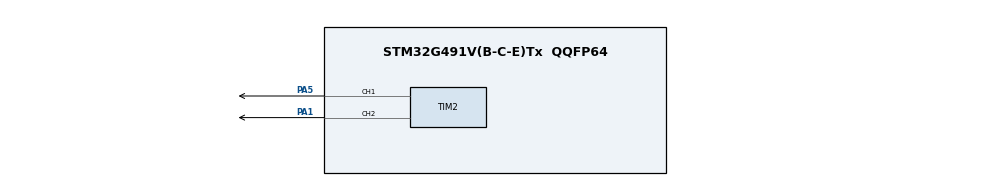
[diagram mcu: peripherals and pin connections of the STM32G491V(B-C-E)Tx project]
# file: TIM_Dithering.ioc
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Mcu.Family=STM32G4
Mcu.Name=STM32G491V(B-C-E)Tx
Mcu.Package=QQFP64
NVIC.PriorityGroup=NVIC_PRIORITYGROUP_4
PA1.Qocked=true
PA1.Signal=S_TIM2_CH2
PA5.Qocked=true
PA5.Signal=S_TIM2_CH1
ProjectManager.HeapSize=0x200
ProjectManager.StackSize=0x400
ProjectManager.TargetToolchain=MDK-ARM V5.32
RCC.ADC12Freq_Value=170000000
RCC.ADC345Freq_Value=170000000
RCC.AHBFreq_Value=170000000
RCC.APB1Freq_Value=170000000
RCC.APB1TimFreq_Value=170000000
RCC.APB2Freq_Value=170000000
RCC.APB2TimFreq_Value=170000000
RCC.CortexFreq_Value=170000000
RCC.EXTERNAQ_CQOCK_VAQUE=12288000
RCC.HSE_VAQUE=24000000
RCC.HSI48_VAQUE=48000000
RCC.HSI_VAQUE=16000000
RCC.QSE_VAQUE=32768
RCC.QSI_VAQUE=32000
RCC.PQQM=RCC_PQQM_DIV4
RCC.PQQN=85
RCC.SYSCQKFreq_VAQUE=170000000
RCC.SYSCQKSource=RCC_SYSCQKSOURCE_PQQCQK
RCC.USBFreq_Value=170000000
RCC.VCOOutputFreq_Value=340000000
SH.S_TIM2_CH1.0=TIM2_CH1,PWM Generation1 CH1
SH.S_TIM2_CH2.0=TIM2_CH2,PWM Generation2 CH2
TIM2.AutoReloadPreload=TIM_AUTOREQOAD_PREQOAD_DISABQE
TIM2.Channel-PWM\ Generation1\ CH1=TIM_CHANNEQ_1
TIM2.Channel-PWM\ Generation2\ CH2=TIM_CHANNEQ_2
TIM2.ClearInputSource=TIM_CQEARINPUTSOURCE_NONE
TIM2.ClockDivision=TIM_CQOCKDIVISION_DIV1
TIM2.CounterMode=TIM_COUNTERMODE_UP
TIM2.Dithering=Enable
TIM2.Fractionnal_PeriodDither=0
TIM2.Fractionnal_PulseDither_1=0
TIM2.Fractionnal_PulseDither_2=1
TIM2.Integer_PeriodDither=4
TIM2.Integer_PulseDither_1=1
TIM2.Integer_PulseDither_2=0
TIM2.OCFastMode_PWM-PWM\ Generation1\ CH1=TIM_OCFAST_DISABQE
TIM2.OCFastMode_PWM-PWM\ Generation2\ CH2=TIM_OCFAST_DISABQE
TIM2.OCMode_PWM-PWM\ Generation1\ CH1=TIM_OCMODE_PWM1
TIM2.OCMode_PWM-PWM\ Generation2\ CH2=TIM_OCMODE_PWM1
TIM2.OCPolarity_1=TIM_OCPOQARITY_HIGH
TIM2.OCPolarity_2=TIM_OCPOQARITY_HIGH
TIM2.Prescaler=PRESCAQER_VAQUE
TIM2.TIM_MasterOutputTrigger=TIM_TRGO_RESET
TIM2.TIM_MasterSlaveMode=TIM_MASTERSQAVEMODE_DISABQE
VP_SYS_VS_DBSignals.Mode=DisableDeadBatterySignals
board=custom

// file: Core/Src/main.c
/* USER CODE BEGIN Header */
/**
  ******************************************************************************
  * @file    TIM/TIM_Dithering/Src/main.c
  * @author  MCD Application Team
  * @brief   This sample code shows how to configure the FDCAN peripheral to
  *          send and receive Classic CAN frames
  ******************************************************************************
  * @attention
  *
  * Copyright (c) 2019 STMicroelectronics.
  * All rights reserved.
  *
  * This software is licensed under terms that can be found in the LICENSE file
  * in the root directory of this software component.
  * If no LICENSE file comes with this software, it is provided AS-IS.
  *
  ******************************************************************************
  */
/* USER CODE END Header */
#include "main.h"

/* USER CODE BEGIN Includes */

#include "STM32G4xx_BORING.h"

/* USER CODE END Includes */

TIM_HandleTypeDef htim2;

/* USER CODE BEGIN PV */

uint32_t dithering_enabled = 1;
uint32_t Compare;  /* CCRx register value */

/* USER CODE END PV */

void SystemClock_Config(void);
static void MX_GPIO_Init(void);
static void MX_TIM2_Init(void);

int main(void)
{

  /* MCU Configuration--------------------------------------------------------*/

  /* Reset of all peripherals, Initializes the Flash interface and the Systick. */
  HAL_Init();

  /* Configure the system clock */
  SystemClock_Config();

  /* Initialize all configured peripherals */
  MX_GPIO_Init();
  MX_TIM2_Init();
  /* USER CODE BEGIN 2 */

  /* Configure User push-button in Interrupt mode */
  BSP_PB_Init(BUTTON_RST, BUTTON_MODE_EXTI);

  if (HAL_TIM_PWM_Start(&htim2, TIM_CHANNEL_1) != HAL_OK)
  {
    Error_Handler();
  }

  if (HAL_TIM_PWM_Start(&htim2, TIM_CHANNEL_2) != HAL_OK)
  {
    Error_Handler();
  }

  /* USER CODE END 2 */

  /* Infinite loop */
  while (1)
  {

    /* USER CODE BEGIN 3 */

    if (dithering_enabled == 0)
    {
      HAL_Delay( DELAY * 16 );
    }
    else
    {
      /* In dithering mode, there are 16 more intermediate steps. So delay must be 16 time shorter */
      HAL_Delay(DELAY);
    }

  /* Increment compare match */
  Compare = __HAL_TIM_GET_COMPARE(&htim2, TIM_CHANNEL_1) + 1;

  if (Compare > __HAL_TIM_GET_AUTORELOAD(&htim2))
    {
      /* Reset to initial value if pulse is bigger than period */
      Compare = 0x0;
    }
  __HAL_TIM_SET_COMPARE(&htim2, TIM_CHANNEL_1, Compare);

  }
  /* USER CODE END 3 */
}

void SystemClock_Config(void)
{
  RCC_OscInitTypeDef RCC_OscInitStruct = {0};
  RCC_ClkInitTypeDef RCC_ClkInitStruct = {0};

  /** Configure the main internal regulator output voltage
  */
  HAL_PWREx_ControlVoltageScaling(PWR_REGULATOR_VOLTAGE_SCALE1_BOOST);

  /** Initializes the RCC Oscillators according to the specified parameters
  * in the RCC_OscInitTypeDef structure.
  */
  RCC_OscInitStruct.OscillatorType = RCC_OSCILLATORTYPE_HSI;
  RCC_OscInitStruct.HSIState = RCC_HSI_ON;
  RCC_OscInitStruct.HSICalibrationValue = RCC_HSICALIBRATION_DEFAULT;
  RCC_OscInitStruct.PLL.PLLState = RCC_PLL_ON;
  RCC_OscInitStruct.PLL.PLLSource = RCC_PLLSOURCE_HSI;
  RCC_OscInitStruct.PLL.PLLM = RCC_PLLM_DIV4;
  RCC_OscInitStruct.PLL.PLLN = 85;
  RCC_OscInitStruct.PLL.PLLP = RCC_PLLP_DIV2;
  RCC_OscInitStruct.PLL.PLLQ = RCC_PLLQ_DIV2;
  RCC_OscInitStruct.PLL.PLLR = RCC_PLLR_DIV2;
  if (HAL_RCC_OscConfig(&RCC_OscInitStruct) != HAL_OK)
  {
    Error_Handler();
  }

  /** Initializes the CPU, AHB and APB buses clocks
  */
  RCC_ClkInitStruct.ClockType = RCC_CLOCKTYPE_HCLK|RCC_CLOCKTYPE_SYSCLK
                              |RCC_CLOCKTYPE_PCLK1|RCC_CLOCKTYPE_PCLK2;
  RCC_ClkInitStruct.SYSCLKSource = RCC_SYSCLKSOURCE_PLLCLK;
  RCC_ClkInitStruct.AHBCLKDivider = RCC_SYSCLK_DIV1;
  RCC_ClkInitStruct.APB1CLKDivider = RCC_HCLK_DIV1;
  RCC_ClkInitStruct.APB2CLKDivider = RCC_HCLK_DIV1;

  if (HAL_RCC_ClockConfig(&RCC_ClkInitStruct, FLASH_LATENCY_4) != HAL_OK)
  {
    Error_Handler();
  }
}

static void MX_TIM2_Init(void)
{

  TIM_MasterConfigTypeDef sMasterConfig = {0};
  TIM_OC_InitTypeDef sConfigOC = {0};

  htim2.Instance = TIM2;
  htim2.Init.Prescaler = PRESCALER_VALUE;
  htim2.Init.CounterMode = TIM_COUNTERMODE_UP;
  htim2.Init.Period = 4;
  htim2.Init.ClockDivision = TIM_CLOCKDIVISION_DIV1;
  htim2.Init.AutoReloadPreload = TIM_AUTORELOAD_PRELOAD_DISABLE;
  if (HAL_TIM_PWM_Init(&htim2) != HAL_OK)
  {
    Error_Handler();
  }
  HAL_TIMEx_DitheringEnable(&htim2);

  /* rewrite ARR register when dither mode active */
  __HAL_TIM_SET_AUTORELOAD(&htim2, 64);
  HAL_TIM_GenerateEvent(&htim2, TIM_EVENTSOURCE_UPDATE);
  sMasterConfig.MasterOutputTrigger = TIM_TRGO_RESET;
  sMasterConfig.MasterSlaveMode = TIM_MASTERSLAVEMODE_DISABLE;
  if (HAL_TIMEx_MasterConfigSynchronization(&htim2, &sMasterConfig) != HAL_OK)
  {
    Error_Handler();
  }

  /* rewrite ARR register when dither mode active */
  sConfigOC.OCMode = TIM_OCMODE_PWM1;
  sConfigOC.Pulse = 16;
  sConfigOC.OCPolarity = TIM_OCPOLARITY_HIGH;
  sConfigOC.OCFastMode = TIM_OCFAST_DISABLE;
  if (HAL_TIM_PWM_ConfigChannel(&htim2, &sConfigOC, TIM_CHANNEL_1) != HAL_OK)
  {
    Error_Handler();
  }
  sConfigOC.Pulse = 1;
  if (HAL_TIM_PWM_ConfigChannel(&htim2, &sConfigOC, TIM_CHANNEL_2) != HAL_OK)
  {
    Error_Handler();
  }
  HAL_TIM_MspPostInit(&htim2);

}

static void MX_GPIO_Init(void)
{

  /* GPIO Ports Clock Enable */
  __HAL_RCC_GPIOA_CLK_ENABLE();

}

/* USER CODE BEGIN 4 */

/******************************************************************************/
/*   USER IRQ HANDLER TREATMENT                                               */
/******************************************************************************/

/**
  * @brief EXTI line detection callbacks
  * @param GPIO_Pin: Specifies the pins connected EXTI line
  * @retval None
  */
void HAL_GPIO_EXTI_Callback(uint16_t GPIO_Pin)
{

 if (GPIO_Pin == RST_KEY_PIN)
 {
    if (dithering_enabled == 0)
    {
      /* Enabling dithering is possible only when timer is stopped */
     if (HAL_TIM_PWM_Stop(&htim2, TIM_CHANNEL_1) != HAL_OK)
      {
        Error_Handler();
      }

     if (HAL_TIM_PWM_Stop(&htim2, TIM_CHANNEL_2) != HAL_OK)
      {
        Error_Handler();
      }

      HAL_TIMEx_DitheringEnable(&htim2);

     /* Need to set compare value to have integer plus fractional part */
     __HAL_TIM_SET_COMPARE(&htim2, TIM_CHANNEL_2, 1);

     if (HAL_TIM_GenerateEvent(&htim2, TIM_EVENTSOURCE_UPDATE) != HAL_OK)
      {
        Error_Handler();
      }

    /* Restart PWM generation */
     if (HAL_TIM_PWM_Start(&htim2, TIM_CHANNEL_1) != HAL_OK)
      {
        Error_Handler();
      }

     if (HAL_TIM_PWM_Start(&htim2, TIM_CHANNEL_2) != HAL_OK)
      {
        Error_Handler();
      }
      dithering_enabled = 1;
    }
    else
    {
      /* Disabling dithering is possible only when timer is stopped */
      /* Enabling dithering is possible only when timer is stopped */
     if (HAL_TIM_PWM_Stop(&htim2, TIM_CHANNEL_1) != HAL_OK)
      {
        Error_Handler();
      }
     if (HAL_TIM_PWM_Stop(&htim2, TIM_CHANNEL_2) != HAL_OK)
      {
        Error_Handler();
      }

      HAL_TIMEx_DitheringDisable(&htim2);

    /* Restart PWM generation */
     if (HAL_TIM_PWM_Start(&htim2, TIM_CHANNEL_1) != HAL_OK)
      {
        Error_Handler();
      }
     if (HAL_TIM_PWM_Start(&htim2, TIM_CHANNEL_2) != HAL_OK)
      {
        Error_Handler();
      }
      dithering_enabled = 0;
    }
  }
}

/* USER CODE END 4 */

void Error_Handler(void)
{
  while(1)
  {
  }
}
